VERSION 5.4 ;
NAMESCASESENSITIVE ON ;
BUSBITCHARS "[]" ;
DIVIDERCHAR "/" ;
UNITS
  DATABASE MICRONS 2000 ;
END UNITS
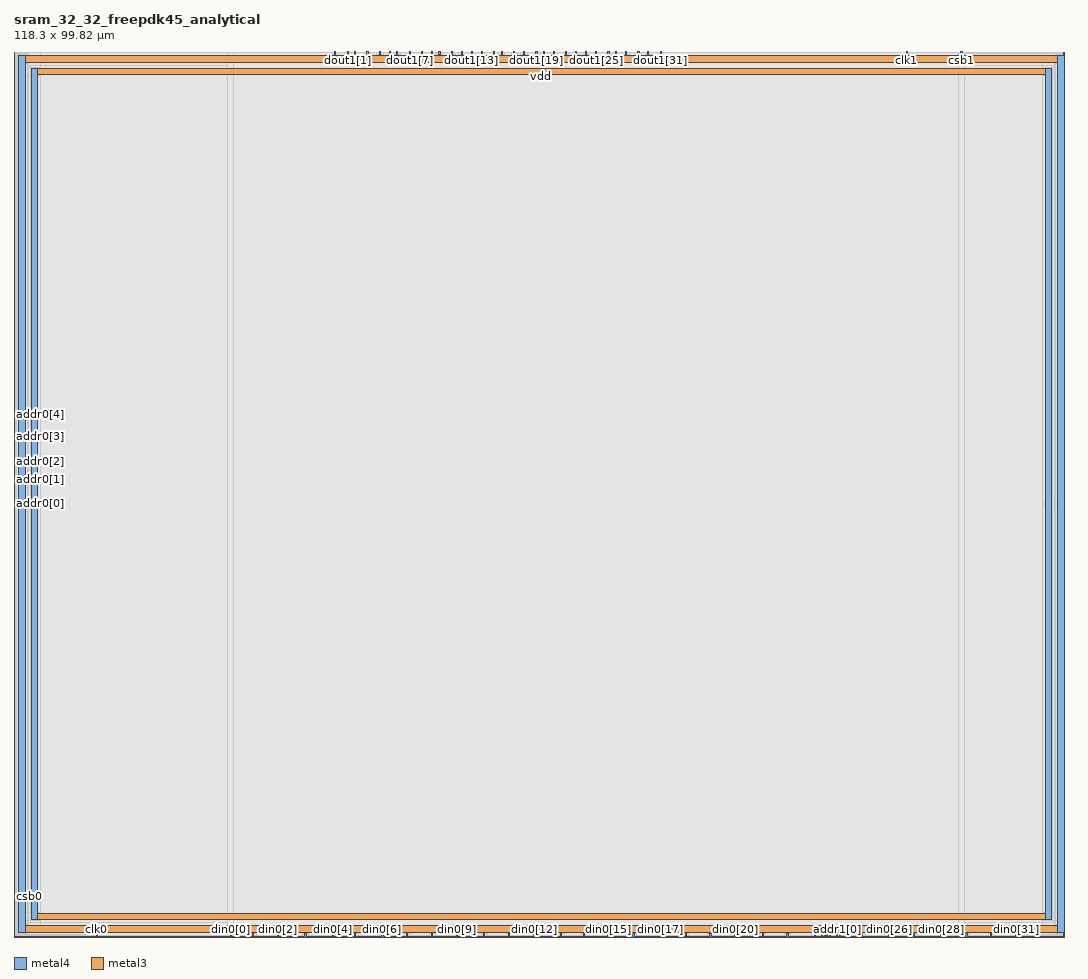
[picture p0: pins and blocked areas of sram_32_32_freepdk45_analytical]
MACRO sram_32_32_freepdk45_analytical
   CLASS BLOCK ;
   SIZE 118.3 BY 99.82 ;
   SYMMETRY X Y R90 ;
   PIN din0[0]
      DIRECTION INPUT ;
      PORT
         LAYER metal4 ;
         RECT  24.36 0.0 24.5 0.42 ;
      END
   END din0[0]
   PIN din0[1]
      DIRECTION INPUT ;
      PORT
         LAYER metal4 ;
         RECT  26.88 0.0 27.02 0.42 ;
      END
   END din0[1]
   PIN din0[2]
      DIRECTION INPUT ;
      PORT
         LAYER metal4 ;
         RECT  29.68 0.0 29.82 0.42 ;
      END
   END din0[2]
   PIN din0[3]
      DIRECTION INPUT ;
      PORT
         LAYER metal4 ;
         RECT  32.76 0.0 32.9 0.42 ;
      END
   END din0[3]
   PIN din0[4]
      DIRECTION INPUT ;
      PORT
         LAYER metal4 ;
         RECT  35.84 0.0 35.98 0.42 ;
      END
   END din0[4]
   PIN din0[5]
      DIRECTION INPUT ;
      PORT
         LAYER metal4 ;
         RECT  38.36 0.0 38.5 0.42 ;
      END
   END din0[5]
   PIN din0[6]
      DIRECTION INPUT ;
      PORT
         LAYER metal4 ;
         RECT  41.44 0.0 41.58 0.42 ;
      END
   END din0[6]
   PIN din0[7]
      DIRECTION INPUT ;
      PORT
         LAYER metal4 ;
         RECT  44.24 0.0 44.38 0.42 ;
      END
   END din0[7]
   PIN din0[8]
      DIRECTION INPUT ;
      PORT
         LAYER metal4 ;
         RECT  47.04 0.0 47.18 0.42 ;
      END
   END din0[8]
   PIN din0[9]
      DIRECTION INPUT ;
      PORT
         LAYER metal4 ;
         RECT  49.84 0.0 49.98 0.42 ;
      END
   END din0[9]
   PIN din0[10]
      DIRECTION INPUT ;
      PORT
         LAYER metal4 ;
         RECT  52.92 0.0 53.06 0.42 ;
      END
   END din0[10]
   PIN din0[11]
      DIRECTION INPUT ;
      PORT
         LAYER metal4 ;
         RECT  55.72 0.0 55.86 0.42 ;
      END
   END din0[11]
   PIN din0[12]
      DIRECTION INPUT ;
      PORT
         LAYER metal4 ;
         RECT  58.52 0.0 58.66 0.42 ;
      END
   END din0[12]
   PIN din0[13]
      DIRECTION INPUT ;
      PORT
         LAYER metal4 ;
         RECT  61.6 0.0 61.74 0.42 ;
      END
   END din0[13]
   PIN din0[14]
      DIRECTION INPUT ;
      PORT
         LAYER metal4 ;
         RECT  64.12 0.0 64.26 0.42 ;
      END
   END din0[14]
   PIN din0[15]
      DIRECTION INPUT ;
      PORT
         LAYER metal4 ;
         RECT  66.92 0.0 67.06 0.42 ;
      END
   END din0[15]
   PIN din0[16]
      DIRECTION INPUT ;
      PORT
         LAYER metal4 ;
         RECT  69.72 0.0 69.86 0.42 ;
      END
   END din0[16]
   PIN din0[17]
      DIRECTION INPUT ;
      PORT
         LAYER metal4 ;
         RECT  72.8 0.0 72.94 0.42 ;
      END
   END din0[17]
   PIN din0[18]
      DIRECTION INPUT ;
      PORT
         LAYER metal4 ;
         RECT  75.6 0.0 75.74 0.42 ;
      END
   END din0[18]
   PIN din0[19]
      DIRECTION INPUT ;
      PORT
         LAYER metal4 ;
         RECT  78.4 0.0 78.54 0.42 ;
      END
   END din0[19]
   PIN din0[20]
      DIRECTION INPUT ;
      PORT
         LAYER metal4 ;
         RECT  81.2 0.0 81.34 0.42 ;
      END
   END din0[20]
   PIN din0[21]
      DIRECTION INPUT ;
      PORT
         LAYER metal4 ;
         RECT  84.28 0.0 84.42 0.42 ;
      END
   END din0[21]
   PIN din0[22]
      DIRECTION INPUT ;
      PORT
         LAYER metal4 ;
         RECT  87.08 0.0 87.22 0.42 ;
      END
   END din0[22]
   PIN din0[23]
      DIRECTION INPUT ;
      PORT
         LAYER metal4 ;
         RECT  90.16 0.0 90.3 0.42 ;
      END
   END din0[23]
   PIN din0[24]
      DIRECTION INPUT ;
      PORT
         LAYER metal4 ;
         RECT  92.96 0.0 93.1 0.42 ;
      END
   END din0[24]
   PIN din0[25]
      DIRECTION INPUT ;
      PORT
         LAYER metal4 ;
         RECT  95.48 0.0 95.62 0.42 ;
      END
   END din0[25]
   PIN din0[26]
      DIRECTION INPUT ;
      PORT
         LAYER metal4 ;
         RECT  98.56 0.0 98.7 0.42 ;
      END
   END din0[26]
   PIN din0[27]
      DIRECTION INPUT ;
      PORT
         LAYER metal4 ;
         RECT  101.36 0.0 101.5 0.42 ;
      END
   END din0[27]
   PIN din0[28]
      DIRECTION INPUT ;
      PORT
         LAYER metal4 ;
         RECT  104.44 0.0 104.58 0.42 ;
      END
   END din0[28]
   PIN din0[29]
      DIRECTION INPUT ;
      PORT
         LAYER metal4 ;
         RECT  107.24 0.0 107.38 0.42 ;
      END
   END din0[29]
   PIN din0[30]
      DIRECTION INPUT ;
      PORT
         LAYER metal4 ;
         RECT  110.04 0.0 110.18 0.42 ;
      END
   END din0[30]
   PIN din0[31]
      DIRECTION INPUT ;
      PORT
         LAYER metal4 ;
         RECT  112.84 0.0 112.98 0.42 ;
      END
   END din0[31]
   PIN addr0[0]
      DIRECTION INPUT ;
      PORT
         LAYER metal3 ;
         RECT  0.0 48.72 0.42 48.86 ;
      END
   END addr0[0]
   PIN addr0[1]
      DIRECTION INPUT ;
      PORT
         LAYER metal3 ;
         RECT  0.0 51.52 0.42 51.66 ;
      END
   END addr0[1]
   PIN addr0[2]
      DIRECTION INPUT ;
      PORT
         LAYER metal3 ;
         RECT  0.0 53.48 0.42 53.62 ;
      END
   END addr0[2]
   PIN addr0[3]
      DIRECTION INPUT ;
      PORT
         LAYER metal3 ;
         RECT  0.0 56.28 0.42 56.42 ;
      END
   END addr0[3]
   PIN addr0[4]
      DIRECTION INPUT ;
      PORT
         LAYER metal3 ;
         RECT  0.0 58.8 0.42 58.94 ;
      END
   END addr0[4]
   PIN addr1[0]
      DIRECTION INPUT ;
      PORT
         LAYER metal4 ;
         RECT  92.68 0.0 92.82 0.42 ;
      END
   END addr1[0]
   PIN addr1[1]
      DIRECTION INPUT ;
      PORT
         LAYER metal4 ;
         RECT  91.0 0.0 91.14 0.42 ;
      END
   END addr1[1]
   PIN addr1[2]
      DIRECTION INPUT ;
      PORT
         LAYER metal4 ;
         RECT  91.28 0.0 91.42 0.42 ;
      END
   END addr1[2]
   PIN addr1[3]
      DIRECTION INPUT ;
      PORT
         LAYER metal4 ;
         RECT  91.56 0.0 91.7 0.42 ;
      END
   END addr1[3]
   PIN addr1[4]
      DIRECTION INPUT ;
      PORT
         LAYER metal4 ;
         RECT  91.84 0.0 91.98 0.42 ;
      END
   END addr1[4]
   PIN csb0
      DIRECTION INPUT ;
      PORT
         LAYER metal3 ;
         RECT  0.0 4.48 0.42 4.62 ;
      END
   END csb0
   PIN csb1
      DIRECTION INPUT ;
      PORT
         LAYER metal4 ;
         RECT  106.68 99.4 106.82 99.82 ;
      END
   END csb1
   PIN clk0
      DIRECTION INPUT ;
      PORT
         LAYER metal4 ;
         RECT  9.24 0.0 9.38 0.42 ;
      END
   END clk0
   PIN clk1
      DIRECTION INPUT ;
      PORT
         LAYER metal4 ;
         RECT  100.52 99.4 100.66 99.82 ;
      END
   END clk1
   PIN dout1[0]
      DIRECTION OUTPUT ;
      PORT
         LAYER metal4 ;
         RECT  36.12 99.4 36.26 99.82 ;
      END
   END dout1[0]
   PIN dout1[1]
      DIRECTION OUTPUT ;
      PORT
         LAYER metal4 ;
         RECT  37.52 99.4 37.66 99.82 ;
      END
   END dout1[1]
   PIN dout1[2]
      DIRECTION OUTPUT ;
      PORT
         LAYER metal4 ;
         RECT  38.36 99.4 38.5 99.82 ;
      END
   END dout1[2]
   PIN dout1[3]
      DIRECTION OUTPUT ;
      PORT
         LAYER metal4 ;
         RECT  39.76 99.4 39.9 99.82 ;
      END
   END dout1[3]
   PIN dout1[4]
      DIRECTION OUTPUT ;
      PORT
         LAYER metal4 ;
         RECT  41.16 99.4 41.3 99.82 ;
      END
   END dout1[4]
   PIN dout1[5]
      DIRECTION OUTPUT ;
      PORT
         LAYER metal4 ;
         RECT  42.28 99.4 42.42 99.82 ;
      END
   END dout1[5]
   PIN dout1[6]
      DIRECTION OUTPUT ;
      PORT
         LAYER metal4 ;
         RECT  43.12 99.4 43.26 99.82 ;
      END
   END dout1[6]
   PIN dout1[7]
      DIRECTION OUTPUT ;
      PORT
         LAYER metal4 ;
         RECT  44.52 99.4 44.66 99.82 ;
      END
   END dout1[7]
   PIN dout1[8]
      DIRECTION OUTPUT ;
      PORT
         LAYER metal4 ;
         RECT  45.92 99.4 46.06 99.82 ;
      END
   END dout1[8]
   PIN dout1[9]
      DIRECTION OUTPUT ;
      PORT
         LAYER metal4 ;
         RECT  47.04 99.4 47.18 99.82 ;
      END
   END dout1[9]
   PIN dout1[10]
      DIRECTION OUTPUT ;
      PORT
         LAYER metal4 ;
         RECT  47.88 99.4 48.02 99.82 ;
      END
   END dout1[10]
   PIN dout1[11]
      DIRECTION OUTPUT ;
      PORT
         LAYER metal4 ;
         RECT  49.28 99.4 49.42 99.82 ;
      END
   END dout1[11]
   PIN dout1[12]
      DIRECTION OUTPUT ;
      PORT
         LAYER metal4 ;
         RECT  50.4 99.4 50.54 99.82 ;
      END
   END dout1[12]
   PIN dout1[13]
      DIRECTION OUTPUT ;
      PORT
         LAYER metal4 ;
         RECT  51.52 99.4 51.66 99.82 ;
      END
   END dout1[13]
   PIN dout1[14]
      DIRECTION OUTPUT ;
      PORT
         LAYER metal4 ;
         RECT  52.64 99.4 52.78 99.82 ;
      END
   END dout1[14]
   PIN dout1[15]
      DIRECTION OUTPUT ;
      PORT
         LAYER metal4 ;
         RECT  54.04 99.4 54.18 99.82 ;
      END
   END dout1[15]
   PIN dout1[16]
      DIRECTION OUTPUT ;
      PORT
         LAYER metal4 ;
         RECT  54.88 99.4 55.02 99.82 ;
      END
   END dout1[16]
   PIN dout1[17]
      DIRECTION OUTPUT ;
      PORT
         LAYER metal4 ;
         RECT  56.28 99.4 56.42 99.82 ;
      END
   END dout1[17]
   PIN dout1[18]
      DIRECTION OUTPUT ;
      PORT
         LAYER metal4 ;
         RECT  57.4 99.4 57.54 99.82 ;
      END
   END dout1[18]
   PIN dout1[19]
      DIRECTION OUTPUT ;
      PORT
         LAYER metal4 ;
         RECT  58.8 99.4 58.94 99.82 ;
      END
   END dout1[19]
   PIN dout1[20]
      DIRECTION OUTPUT ;
      PORT
         LAYER metal4 ;
         RECT  59.64 99.4 59.78 99.82 ;
      END
   END dout1[20]
   PIN dout1[21]
      DIRECTION OUTPUT ;
      PORT
         LAYER metal4 ;
         RECT  60.76 99.4 60.9 99.82 ;
      END
   END dout1[21]
   PIN dout1[22]
      DIRECTION OUTPUT ;
      PORT
         LAYER metal4 ;
         RECT  62.16 99.4 62.3 99.82 ;
      END
   END dout1[22]
   PIN dout1[23]
      DIRECTION OUTPUT ;
      PORT
         LAYER metal4 ;
         RECT  63.28 99.4 63.42 99.82 ;
      END
   END dout1[23]
   PIN dout1[24]
      DIRECTION OUTPUT ;
      PORT
         LAYER metal4 ;
         RECT  64.4 99.4 64.54 99.82 ;
      END
   END dout1[24]
   PIN dout1[25]
      DIRECTION OUTPUT ;
      PORT
         LAYER metal4 ;
         RECT  65.52 99.4 65.66 99.82 ;
      END
   END dout1[25]
   PIN dout1[26]
      DIRECTION OUTPUT ;
      PORT
         LAYER metal4 ;
         RECT  66.92 99.4 67.06 99.82 ;
      END
   END dout1[26]
   PIN dout1[27]
      DIRECTION OUTPUT ;
      PORT
         LAYER metal4 ;
         RECT  67.76 99.4 67.9 99.82 ;
      END
   END dout1[27]
   PIN dout1[28]
      DIRECTION OUTPUT ;
      PORT
         LAYER metal4 ;
         RECT  68.88 99.4 69.02 99.82 ;
      END
   END dout1[28]
   PIN dout1[29]
      DIRECTION OUTPUT ;
      PORT
         LAYER metal4 ;
         RECT  70.28 99.4 70.42 99.82 ;
      END
   END dout1[29]
   PIN dout1[30]
      DIRECTION OUTPUT ;
      PORT
         LAYER metal4 ;
         RECT  71.4 99.4 71.54 99.82 ;
      END
   END dout1[30]
   PIN dout1[31]
      DIRECTION OUTPUT ;
      PORT
         LAYER metal4 ;
         RECT  72.8 99.4 72.94 99.82 ;
      END
   END dout1[31]
   PIN vdd
      DIRECTION INOUT ;
      USE POWER ; 
      SHAPE ABUTMENT ; 
      PORT
         LAYER metal4 ;
         RECT  116.2 1.96 116.9 97.86 ;
         LAYER metal3 ;
         RECT  1.96 97.16 116.9 97.86 ;
         LAYER metal3 ;
         RECT  1.96 1.96 116.9 2.66 ;
         LAYER metal4 ;
         RECT  1.96 1.96 2.66 97.86 ;
      END
   END vdd
   PIN gnd
      DIRECTION INOUT ;
      USE GROUND ; 
      SHAPE ABUTMENT ; 
      PORT
         LAYER metal3 ;
         RECT  0.56 0.56 118.3 1.26 ;
         LAYER metal4 ;
         RECT  117.6 0.56 118.3 99.26 ;
         LAYER metal3 ;
         RECT  0.56 98.56 118.3 99.26 ;
         LAYER metal4 ;
         RECT  0.56 0.56 1.26 99.26 ;
      END
   END gnd
   OBS
   LAYER  metal1 ;
      RECT  0.14 0.14 118.16 99.68 ;
   LAYER  metal2 ;
      RECT  0.14 0.14 118.16 99.68 ;
   LAYER  metal3 ;
      RECT  0.56 48.58 118.16 49.0 ;
      RECT  0.14 49.0 0.56 51.38 ;
      RECT  0.14 51.8 0.56 53.34 ;
      RECT  0.14 53.76 0.56 56.14 ;
      RECT  0.14 56.56 0.56 58.66 ;
      RECT  0.14 4.76 0.56 48.58 ;
      RECT  0.56 49.0 1.82 97.02 ;
      RECT  0.56 97.02 1.82 98.0 ;
      RECT  1.82 49.0 117.04 97.02 ;
      RECT  117.04 49.0 118.16 97.02 ;
      RECT  117.04 97.02 118.16 98.0 ;
      RECT  0.56 1.82 1.82 2.8 ;
      RECT  0.56 2.8 1.82 48.58 ;
      RECT  1.82 2.8 117.04 48.58 ;
      RECT  117.04 1.82 118.16 2.8 ;
      RECT  117.04 2.8 118.16 48.58 ;
      RECT  0.14 0.14 0.42 0.42 ;
      RECT  0.14 0.42 0.42 1.4 ;
      RECT  0.14 1.4 0.42 4.34 ;
      RECT  0.42 0.14 0.56 0.42 ;
      RECT  0.42 1.4 0.56 4.34 ;
      RECT  0.56 0.14 1.82 0.42 ;
      RECT  0.56 1.4 1.82 1.82 ;
      RECT  1.82 0.14 117.04 0.42 ;
      RECT  1.82 1.4 117.04 1.82 ;
      RECT  117.04 0.14 118.16 0.42 ;
      RECT  117.04 1.4 118.16 1.82 ;
      RECT  0.14 59.08 0.42 98.42 ;
      RECT  0.14 98.42 0.42 99.4 ;
      RECT  0.14 99.4 0.42 99.68 ;
      RECT  0.42 59.08 0.56 98.42 ;
      RECT  0.42 99.4 0.56 99.68 ;
      RECT  0.56 98.0 1.82 98.42 ;
      RECT  0.56 99.4 1.82 99.68 ;
      RECT  1.82 98.0 117.04 98.42 ;
      RECT  1.82 99.4 117.04 99.68 ;
      RECT  117.04 98.0 118.16 98.42 ;
      RECT  117.04 99.4 118.16 99.68 ;
   LAYER  metal4 ;
      RECT  24.08 0.7 24.78 99.68 ;
      RECT  24.78 0.14 26.6 0.7 ;
      RECT  27.3 0.14 29.4 0.7 ;
      RECT  30.1 0.14 32.48 0.7 ;
      RECT  33.18 0.14 35.56 0.7 ;
      RECT  36.26 0.14 38.08 0.7 ;
      RECT  38.78 0.14 41.16 0.7 ;
      RECT  41.86 0.14 43.96 0.7 ;
      RECT  44.66 0.14 46.76 0.7 ;
      RECT  47.46 0.14 49.56 0.7 ;
      RECT  50.26 0.14 52.64 0.7 ;
      RECT  53.34 0.14 55.44 0.7 ;
      RECT  56.14 0.14 58.24 0.7 ;
      RECT  58.94 0.14 61.32 0.7 ;
      RECT  62.02 0.14 63.84 0.7 ;
      RECT  64.54 0.14 66.64 0.7 ;
      RECT  67.34 0.14 69.44 0.7 ;
      RECT  70.14 0.14 72.52 0.7 ;
      RECT  73.22 0.14 75.32 0.7 ;
      RECT  76.02 0.14 78.12 0.7 ;
      RECT  78.82 0.14 80.92 0.7 ;
      RECT  81.62 0.14 84.0 0.7 ;
      RECT  84.7 0.14 86.8 0.7 ;
      RECT  87.5 0.14 89.88 0.7 ;
      RECT  93.38 0.14 95.2 0.7 ;
      RECT  95.9 0.14 98.28 0.7 ;
      RECT  98.98 0.14 101.08 0.7 ;
      RECT  101.78 0.14 104.16 0.7 ;
      RECT  104.86 0.14 106.96 0.7 ;
      RECT  107.66 0.14 109.76 0.7 ;
      RECT  110.46 0.14 112.56 0.7 ;
      RECT  90.58 0.14 90.72 0.7 ;
      RECT  92.26 0.14 92.4 0.7 ;
      RECT  24.78 0.7 106.4 99.12 ;
      RECT  106.4 0.7 107.1 99.12 ;
      RECT  9.66 0.14 24.08 0.7 ;
      RECT  100.94 99.12 106.4 99.68 ;
      RECT  24.78 99.12 35.84 99.68 ;
      RECT  36.54 99.12 37.24 99.68 ;
      RECT  37.94 99.12 38.08 99.68 ;
      RECT  38.78 99.12 39.48 99.68 ;
      RECT  40.18 99.12 40.88 99.68 ;
      RECT  41.58 99.12 42.0 99.68 ;
      RECT  42.7 99.12 42.84 99.68 ;
      RECT  43.54 99.12 44.24 99.68 ;
      RECT  44.94 99.12 45.64 99.68 ;
      RECT  46.34 99.12 46.76 99.68 ;
      RECT  47.46 99.12 47.6 99.68 ;
      RECT  48.3 99.12 49.0 99.68 ;
      RECT  49.7 99.12 50.12 99.68 ;
      RECT  50.82 99.12 51.24 99.68 ;
      RECT  51.94 99.12 52.36 99.68 ;
      RECT  53.06 99.12 53.76 99.68 ;
      RECT  54.46 99.12 54.6 99.68 ;
      RECT  55.3 99.12 56.0 99.68 ;
      RECT  56.7 99.12 57.12 99.68 ;
      RECT  57.82 99.12 58.52 99.68 ;
      RECT  59.22 99.12 59.36 99.68 ;
      RECT  60.06 99.12 60.48 99.68 ;
      RECT  61.18 99.12 61.88 99.68 ;
      RECT  62.58 99.12 63.0 99.68 ;
      RECT  63.7 99.12 64.12 99.68 ;
      RECT  64.82 99.12 65.24 99.68 ;
      RECT  65.94 99.12 66.64 99.68 ;
      RECT  67.34 99.12 67.48 99.68 ;
      RECT  68.18 99.12 68.6 99.68 ;
      RECT  69.3 99.12 70.0 99.68 ;
      RECT  70.7 99.12 71.12 99.68 ;
      RECT  71.82 99.12 72.52 99.68 ;
      RECT  73.22 99.12 100.24 99.68 ;
      RECT  107.1 0.7 115.92 1.68 ;
      RECT  107.1 1.68 115.92 98.14 ;
      RECT  107.1 98.14 115.92 99.12 ;
      RECT  115.92 0.7 117.18 1.68 ;
      RECT  115.92 98.14 117.18 99.12 ;
      RECT  1.68 0.7 2.94 1.68 ;
      RECT  1.68 98.14 2.94 99.68 ;
      RECT  2.94 0.7 24.08 1.68 ;
      RECT  2.94 1.68 24.08 98.14 ;
      RECT  2.94 98.14 24.08 99.68 ;
      RECT  113.26 0.14 117.32 0.28 ;
      RECT  113.26 0.28 117.32 0.7 ;
      RECT  117.32 0.14 118.16 0.28 ;
      RECT  107.1 99.12 117.32 99.54 ;
      RECT  107.1 99.54 117.32 99.68 ;
      RECT  117.32 99.54 118.16 99.68 ;
      RECT  117.18 0.7 117.32 1.68 ;
      RECT  117.18 1.68 117.32 98.14 ;
      RECT  117.18 98.14 117.32 99.12 ;
      RECT  0.14 0.14 0.28 0.28 ;
      RECT  0.14 0.28 0.28 0.7 ;
      RECT  0.28 0.14 1.54 0.28 ;
      RECT  1.54 0.14 8.96 0.28 ;
      RECT  1.54 0.28 8.96 0.7 ;
      RECT  0.14 0.7 0.28 1.68 ;
      RECT  1.54 0.7 1.68 1.68 ;
      RECT  0.14 1.68 0.28 98.14 ;
      RECT  1.54 1.68 1.68 98.14 ;
      RECT  0.14 98.14 0.28 99.54 ;
      RECT  0.14 99.54 0.28 99.68 ;
      RECT  0.28 99.54 1.54 99.68 ;
      RECT  1.54 98.14 1.68 99.54 ;
      RECT  1.54 99.54 1.68 99.68 ;
   END
END    sram_32_32_freepdk45_analytical
END    LIBRARY
